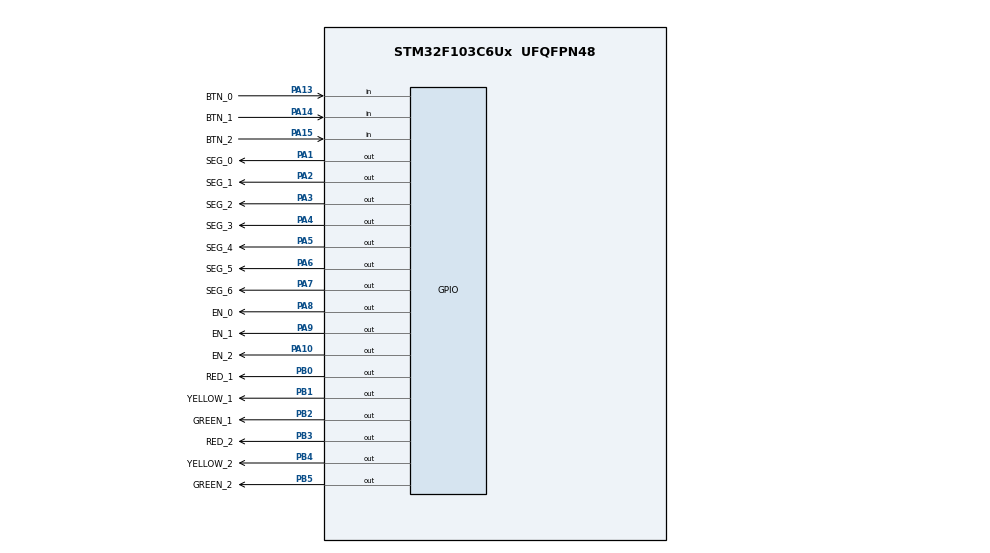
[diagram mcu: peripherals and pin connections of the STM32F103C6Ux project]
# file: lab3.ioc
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Mcu.Family=STM32F1
Mcu.Name=STM32F103C6Ux
Mcu.Package=UFQFPN48
NVIC.PriorityGroup=NVIC_PRIORITYGROUP_4
PA1.GPIO_Label=SEG_0
PA1.Signal=GPIO_Output
PA10.GPIO_Label=EN_2
PA10.Signal=GPIO_Output
PA13.GPIO_Label=BTN_0
PA13.GPIO_PuPd=GPIO_PULLUP
PA13.Signal=GPIO_Input
PA14.GPIO_Label=BTN_1
PA14.GPIO_PuPd=GPIO_PULLUP
PA14.Signal=GPIO_Input
PA15.GPIO_Label=BTN_2
PA15.Signal=GPIO_Input
PA2.GPIO_Label=SEG_1
PA2.Signal=GPIO_Output
PA3.GPIO_Label=SEG_2
PA3.Signal=GPIO_Output
PA4.GPIO_Label=SEG_3
PA4.Signal=GPIO_Output
PA5.GPIO_Label=SEG_4
PA5.Signal=GPIO_Output
PA6.GPIO_Label=SEG_5
PA6.Signal=GPIO_Output
PA7.GPIO_Label=SEG_6
PA7.Signal=GPIO_Output
PA8.GPIO_Label=EN_0
PA8.Signal=GPIO_Output
PA9.GPIO_Label=EN_1
PA9.Signal=GPIO_Output
PB0.GPIO_Label=RED_1
PB0.Signal=GPIO_Output
PB1.GPIO_Label=YELLOW_1
PB1.Signal=GPIO_Output
PB2.GPIO_Label=GREEN_1
PB2.Signal=GPIO_Output
PB3.GPIO_Label=RED_2
PB3.Signal=GPIO_Output
PB4.GPIO_Label=YELLOW_2
PB4.Signal=GPIO_Output
PB5.GPIO_Label=GREEN_2
PB5.Signal=GPIO_Output
ProjectManager.HeapSize=0x200
ProjectManager.StackSize=0x400
ProjectManager.TargetToolchain=STM32CubeIDE
RCC.APB1Freq_Value=8000000
RCC.APB2Freq_Value=8000000
TIM2.Period=9
TIM2.Prescaler=7999
VP_TIM2_VS_ClockSourceINT.Mode=Internal
board=custom

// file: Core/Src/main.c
/* USER CODE BEGIN Header */
/**
  ******************************************************************************
  * @file           : main.c
  * @brief          : Main program body
  ******************************************************************************
  * @attention
  *
  * Copyright (c) 2024 STMicroelectronics.
  * All rights reserved.
  *
  * This software is licensed under terms that can be found in the LICENSE file
  * in the root directory of this software component.
  * If no LICENSE file comes with this software, it is provided AS-IS.
  *
  ******************************************************************************
  */
/* USER CODE END Header */
#include "main.h"

TIM_HandleTypeDef htim2;

void SystemClock_Config(void);
static void MX_GPIO_Init(void);
static void MX_TIM2_Init(void);

int main(void)
{

  /* MCU Configuration--------------------------------------------------------*/

  /* Reset of all peripherals, Initializes the Flash interface and the Systick. */
  HAL_Init();

  /* Configure the system clock */
  SystemClock_Config();

  /* Initialize all configured peripherals */
  MX_GPIO_Init();
  MX_TIM2_Init();
  /* USER CODE BEGIN 2 */
  HAL_TIM_Base_Start_IT(&htim2);
  Scheduler_Init();
  light_1 = INIT;
  light_2 = INIT;
  modify = INIT_SETTING;
  mode = NORMAL_MODE;
  Scheduler_Add_Task(&updateTimer, 1, 1);
  Scheduler_Add_Task(&modify_run, 1, 1);
  Scheduler_Add_Task(&automatic_run, 1, 1);
  Scheduler_Add_Task(&button_reading, 1, 1);
  Scheduler_Add_Task(&scanning_seg_led, 3, freq_to_tick(FREQ_SCANNING));
//  Scheduler_Add_Task(&update_7seg_buffer_time, 7, ONE_SECOND);
  /* USER CODE END 2 */

  /* Infinite loop */
  /* USER CODE BEGIN WHILE */
  while (1)
  {
    Scheduler_Dispatch_Tasks();
    /* USER CODE END WHILE */

  }
}

void SystemClock_Config(void)
{
  RCC_OscInitTypeDef RCC_OscInitStruct = {0};
  RCC_ClkInitTypeDef RCC_ClkInitStruct = {0};

  /** Initializes the RCC Oscillators according to the specified parameters
  * in the RCC_OscInitTypeDef structure.
  */
  RCC_OscInitStruct.OscillatorType = RCC_OSCILLATORTYPE_HSI;
  RCC_OscInitStruct.HSIState = RCC_HSI_ON;
  RCC_OscInitStruct.HSICalibrationValue = RCC_HSICALIBRATION_DEFAULT;
  RCC_OscInitStruct.PLL.PLLState = RCC_PLL_NONE;
  if (HAL_RCC_OscConfig(&RCC_OscInitStruct) != HAL_OK)
  {
    Error_Handler();
  }

  /** Initializes the CPU, AHB and APB buses clocks
  */
  RCC_ClkInitStruct.ClockType = RCC_CLOCKTYPE_HCLK|RCC_CLOCKTYPE_SYSCLK
                              |RCC_CLOCKTYPE_PCLK1|RCC_CLOCKTYPE_PCLK2;
  RCC_ClkInitStruct.SYSCLKSource = RCC_SYSCLKSOURCE_HSI;
  RCC_ClkInitStruct.AHBCLKDivider = RCC_SYSCLK_DIV1;
  RCC_ClkInitStruct.APB1CLKDivider = RCC_HCLK_DIV1;
  RCC_ClkInitStruct.APB2CLKDivider = RCC_HCLK_DIV1;

  if (HAL_RCC_ClockConfig(&RCC_ClkInitStruct, FLASH_LATENCY_0) != HAL_OK)
  {
    Error_Handler();
  }
}

static void MX_TIM2_Init(void)
{

  TIM_ClockConfigTypeDef sClockSourceConfig = {0};
  TIM_MasterConfigTypeDef sMasterConfig = {0};

  htim2.Instance = TIM2;
  htim2.Init.Prescaler = 7999;
  htim2.Init.CounterMode = TIM_COUNTERMODE_UP;
  htim2.Init.Period = 9;
  htim2.Init.ClockDivision = TIM_CLOCKDIVISION_DIV1;
  htim2.Init.AutoReloadPreload = TIM_AUTORELOAD_PRELOAD_DISABLE;
  if (HAL_TIM_Base_Init(&htim2) != HAL_OK)
  {
    Error_Handler();
  }
  sClockSourceConfig.ClockSource = TIM_CLOCKSOURCE_INTERNAL;
  if (HAL_TIM_ConfigClockSource(&htim2, &sClockSourceConfig) != HAL_OK)
  {
    Error_Handler();
  }
  sMasterConfig.MasterOutputTrigger = TIM_TRGO_RESET;
  sMasterConfig.MasterSlaveMode = TIM_MASTERSLAVEMODE_DISABLE;
  if (HAL_TIMEx_MasterConfigSynchronization(&htim2, &sMasterConfig) != HAL_OK)
  {
    Error_Handler();
  }

}

static void MX_GPIO_Init(void)
{
  GPIO_InitTypeDef GPIO_InitStruct = {0};

  /* GPIO Ports Clock Enable */
  __HAL_RCC_GPIOA_CLK_ENABLE();
  __HAL_RCC_GPIOB_CLK_ENABLE();

  /*Configure GPIO pin Output Level */
  HAL_GPIO_WritePin(GPIOA, SEG_0_Pin|SEG_1_Pin|SEG_2_Pin|SEG_3_Pin
                          |SEG_4_Pin|SEG_5_Pin|SEG_6_Pin|EN_0_Pin
                          |EN_1_Pin|EN_2_Pin|EN_3_Pin|EN_4_Pin, GPIO_PIN_RESET);

  /*Configure GPIO pin Output Level */
  HAL_GPIO_WritePin(GPIOB, RED_1_Pin|YELLOW_1_Pin|GREEN_1_Pin|RED_2_Pin
                          |YELLOW_2_Pin|GREEN_2_Pin, GPIO_PIN_RESET);

  /*Configure GPIO pins : SEG_0_Pin SEG_1_Pin SEG_2_Pin SEG_3_Pin
                           SEG_4_Pin SEG_5_Pin SEG_6_Pin EN_0_Pin
                           EN_1_Pin EN_2_Pin EN_3_Pin EN_4_Pin */
  GPIO_InitStruct.Pin = SEG_0_Pin|SEG_1_Pin|SEG_2_Pin|SEG_3_Pin
                          |SEG_4_Pin|SEG_5_Pin|SEG_6_Pin|EN_0_Pin
                          |EN_1_Pin|EN_2_Pin|EN_3_Pin|EN_4_Pin;
  GPIO_InitStruct.Mode = GPIO_MODE_OUTPUT_PP;
  GPIO_InitStruct.Pull = GPIO_NOPULL;
  GPIO_InitStruct.Speed = GPIO_SPEED_FREQ_LOW;
  HAL_GPIO_Init(GPIOA, &GPIO_InitStruct);

  /*Configure GPIO pins : RED_1_Pin YELLOW_1_Pin GREEN_1_Pin RED_2_Pin
                           YELLOW_2_Pin GREEN_2_Pin */
  GPIO_InitStruct.Pin = RED_1_Pin|YELLOW_1_Pin|GREEN_1_Pin|RED_2_Pin
                          |YELLOW_2_Pin|GREEN_2_Pin;
  GPIO_InitStruct.Mode = GPIO_MODE_OUTPUT_PP;
  GPIO_InitStruct.Pull = GPIO_NOPULL;
  GPIO_InitStruct.Speed = GPIO_SPEED_FREQ_LOW;
  HAL_GPIO_Init(GPIOB, &GPIO_InitStruct);

  /*Configure GPIO pins : BTN_0_Pin BTN_1_Pin BTN_2_Pin */
  GPIO_InitStruct.Pin = BTN_0_Pin|BTN_1_Pin|BTN_2_Pin;
  GPIO_InitStruct.Mode = GPIO_MODE_INPUT;
  GPIO_InitStruct.Pull = GPIO_PULLUP;
  HAL_GPIO_Init(GPIOA, &GPIO_InitStruct);

}

/* USER CODE BEGIN 4 */
void HAL_TIM_PeriodElapsedCallback(TIM_HandleTypeDef *htim)
{
    if (htim->Instance == TIM2)
    {
        Scheduler_Update();
    }
}
/* USER CODE END 4 */

void Error_Handler(void)
{
  __disable_irq();
  while (1)
  {
  }
}
